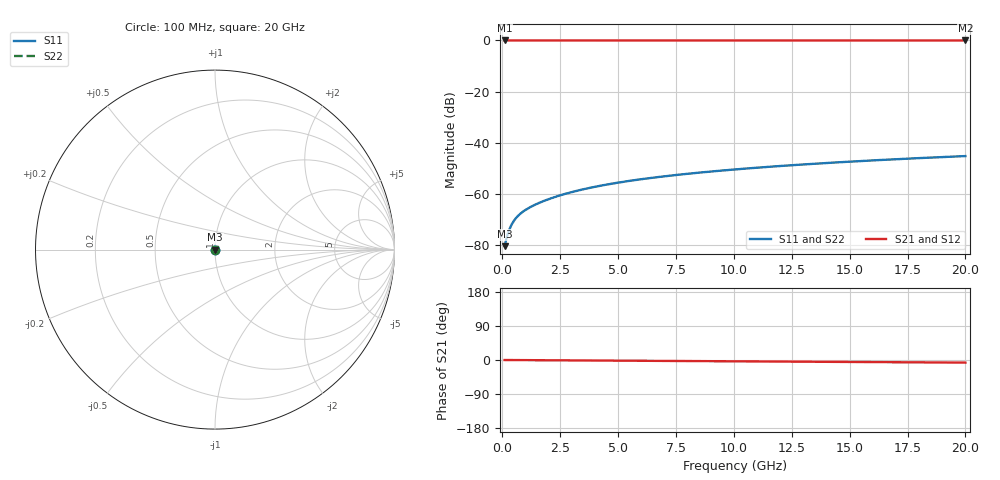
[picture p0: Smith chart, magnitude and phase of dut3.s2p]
! Touchstone file exported from HFSS 2026.1.0
!  File:  C:/ffzhzh/LocalFiles/Ansys_Project_Files/temp_test_TSV_3_1782977936_45748.aedt
!  Generated:  03:40:40 PM Jul  2, 2026
!  Design:  TSV
!  Project:  temp_test_TSV_3_1782977936_45748
! Variables:
!  h_bsmrdl = 2um
!  h_ox = 20um
!  h_rdl = 5um
!  h_sub = 64.56um
!  h_tmrdl = 5um
!  h_tsv = 64.56um
!  h_via = 3um
!  l_bsmrdl = 300um
!  l_sub = 426.38um
!  l_tmrdl = 200um
!  m_sub = 200um
!  pitch = 54.68um
!  r_tsv = 13.19um
!  s_tmrdl = 10um
!  w_bsmrdl = 18um
!  w_sub = 500um
!  w_tmrdl = 12um
!  x_tsv_center1 = 206um
!  x_tsv_center2 = 524um
!  x_tsv_center3 = 736um
!  x_tsv_center4 = 1054um
!  x_tsv_center5 = 1266um
!  x_tsv_center6 = 1584um
# GHz S MA R 50.000000
! Terminal data exported
! Port[1] = TSV1_1_T1
! Port[2] = TSV1_1_T2
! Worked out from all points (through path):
!   200 points, 100 MHz to 20 GHz, reference 50 ohm
!   highest |S21| = 0.00 dB at 100 MHz (marker M1); lowest = 0.0 dB at 20 GHz (marker M2)
!   lowest |S11| = -80.5 dB at 100 MHz (marker M3), VSWR 1.00, Z = 50 + j0.00606 ohm
!   |S11| at or under -10 dB: start of sweep to end of sweep
!   |S22| runs from -80.5 to -45.2 dB; largest |S21 - S12| = 3.7e-15
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0.1  9.451e-05 39.9  0.9999 -0.0  0.9999 -0.0  9.451e-05 39.9
! Gamma 0 0 0 0
! Port Impedance 50 0 50 0
0.2  0.0001447 55.0  0.9999 -0.1  0.9999 -0.1  0.0001447 55.0
0.3  0.0001981 60.2  0.9999 -0.1  0.9999 -0.1  0.0001981 60.2
0.4  0.0002489 62.1  0.9999 -0.1  0.9999 -0.1  0.0002489 62.1
0.5  0.0002959 62.7  0.9999 -0.2  0.9999 -0.2  0.0002959 62.7
0.6  0.0003388 63.0  0.9998 -0.2  0.9998 -0.2  0.0003388 63.0
0.7  0.0003784 63.1  0.9998 -0.2  0.9998 -0.2  0.0003784 63.1
0.9  0.0004498 63.5  0.9998 -0.3  0.9998 -0.3  0.0004498 63.5
1.1  0.0005148 64.1  0.9998 -0.4  0.9998 -0.4  0.0005148 64.1
1.3  0.0005766 64.9  0.9998 -0.5  0.9998 -0.5  0.0005766 64.9
1.6  0.0006665 66.2  0.9997 -0.6  0.9997 -0.6  0.0006665 66.2
1.9  0.0007555 67.5  0.9997 -0.7  0.9997 -0.7  0.0007555 67.5
2.6  0.0009625 69.7  0.9997 -0.9  0.9997 -0.9  0.0009625 69.7
3.5  0.001226 71.4  0.9996 -1.2  0.9996 -1.2  0.001226 71.4
4.2  0.001428 72.3  0.9996 -1.5  0.9996 -1.5  0.001428 72.3
5  0.001654 72.9  0.9996 -1.7  0.9996 -1.7  0.001653 72.9
6.8  0.002145 73.8  0.9995 -2.4  0.9995 -2.4  0.002145 73.8
8.3  0.002542 74.2  0.9994 -2.9  0.9994 -2.9  0.002542 74.2
10.1  0.00301 74.5  0.9994 -3.5  0.9994 -3.5  0.00301 74.5
13.4  0.003852 74.6  0.9993 -4.6  0.9993 -4.6  0.003852 74.6
16.7  0.004674 74.4  0.9992 -5.7  0.9992 -5.7  0.004674 74.4
20  0.005473 73.8  0.9991 -6.9  0.9991 -6.9  0.005473 73.8
